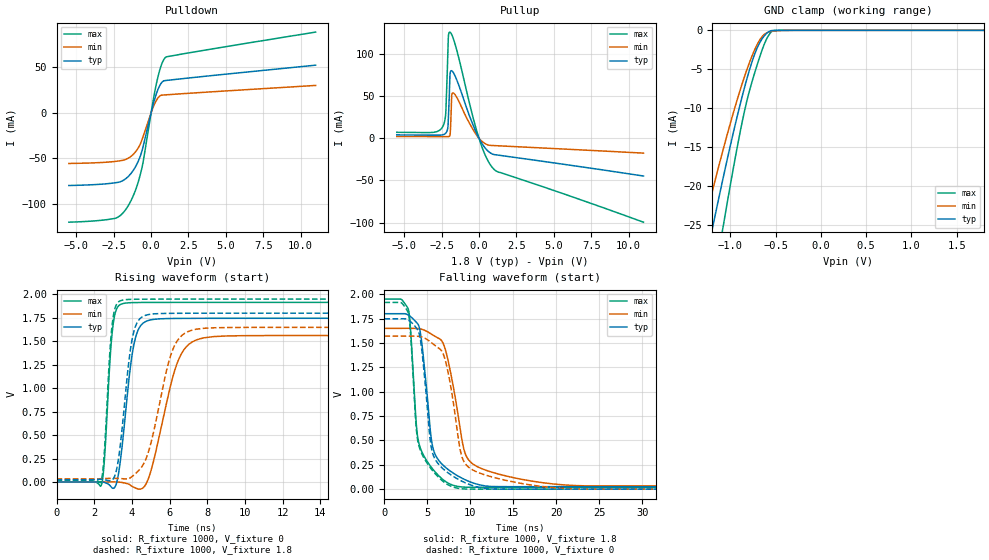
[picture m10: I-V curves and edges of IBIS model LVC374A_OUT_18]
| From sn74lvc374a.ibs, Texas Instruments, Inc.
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[Model]   LVC374A_OUT_18
Model_type  3-state
Enable   Active-Low
Vref =   0
Rref =   1000
Cref =   30p
Vmeas =   0.9
| variable   typ   min   max
C_comp   5.41pF   5.26pF   5.89pF
| C_pullup   6.96pF   5.99pF   7.49pF
| C_pulldown   6.80pF   5.31pF   7.92pF
| C_tri-state   5.41pF   5.26pF   5.89pF
[Temperature Range]   40   100   -40
| Ambient temperature   25   85   -40
[Voltage range]   1.8   1.65   1.95
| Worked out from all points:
|   slope of the pulldown table from 0 to 0.27 V, typ, clamps not added: 16.1 ohm
|   slope of the pullup table from 0 to 0.27 V, typ, clamps not added: 33.2 ohm
|   GND clamp passes 1 mA (typ) near -0.65 V on its own axis
|   rising waveform, R_fixture 1000, V_fixture 0: 20-80 % time 582ps typ, 1.12ns min, 337ps max; typ from 0 V to 1.75 V
|   falling waveform, R_fixture 1000, V_fixture 1.8: 20-80 % time 1.37ns typ, 2.05ns min, 1.16ns max; typ from 1.8 V to 0.026 V
|   rising waveform, R_fixture 1000, V_fixture 1.8: 20-80 % time 572ps typ, 1.09ns min, 332ps max; typ from 0.025 V to 1.8 V
|   falling waveform, R_fixture 1000, V_fixture 0: 20-80 % time 1.3ns typ, 1.83ns min, 1.16ns max; typ from 1.75 V to 0 V
[GND Clamp]
| LVC374A_OUT_18
|   Voltage   I(typ)   I(min)   I(max)
-5.5V     -311.6mA   -259.3mA   -396.4mA
-1.3V     -31.17mA   -25.35mA   -40.84mA
-1.215V   -26.32mA   -21.36mA   -34.65mA
-1.175V   -24.09mA   -19.52mA   -31.79mA
-1.1V     -19.99mA   -16.16mA   -26.53mA
-1.06V    -17.86mA   -14.42mA   -23.79mA
-880mV    -8.928mA   -7.206mA   -12.33mA
-765mV    -4.161mA   -3.399mA   -6.744mA
-655mV    -1.171mA   -880.6uA   -2.683mA
-590mV    -295.4uA   -275.9uA   -882.9uA
-540mV    -28.91uA   -111.9uA   -128.1uA
1.8V      35.26pA    10.02nA    -1.245nA
[Pulldown]
| LVC374A_OUT_18
|   Voltage   I(typ)   I(min)   I(max)
-5.5V     -79.86mA   -55.62mA   -120.2mA
-2.405V   -76.84mA   -53.37mA   -115.9mA
-1.95V    -74.97mA   -52.33mA   -111.2mA
-1.505V   -69.56mA   -49.58mA   -101.4mA
-1.04V    -59.1mA    -42.78mA   -84.85mA
-665mV    -44.74mA   -31.97mA   -64.09mA
-520mV    -36.04mA   -25.31mA   -52.64mA
70mV      4.78mA     3.284mA    7.076mA
355mV     21.12mA    13.82mA    32.13mA
675mV     32.63mA    19.38mA    52.09mA
970mV     35.59mA    19.83mA    61.12mA
11V       52.47mA    30.19mA    88.86mA
[Pullup]
| LVC374A_OUT_18
|   Voltage   I(typ)   I(min)   I(max)
-5.5V     4.132mA    2.28mA     7.221mA
-2.42V    4.318mA    2.093mA    14.19mA
-2.225V   6.276mA    2.078mA    30.14mA
-2.085V   12.97mA    2.077mA    101.8mA
-2.045V   25.72mA    2.109mA    121.9mA
-1.945V   74.01mA    3.627mA    126.3mA
-1.895V   79.92mA    16.59mA    125.6mA
-1.83V    80.38mA    50.38mA    123.6mA
-1.73V    78.5mA     54.05mA    119.2mA
-25mV     874.8uA    531.1uA    1.42mA
995mV     -19.19mA   -8.546mA   -36.64mA
11V       -44.72mA   -17.52mA   -99.61mA
[Ramp]
| LVC374A_OUT_18
| variable   typ   min   max
dV/dt_r   1.09/6.04E-10   0.98/1.16E-09   1.18/3.48E-10
dV/dt_f   1.06/1.37E-09   0.97/2.05E-09   1.16/1.16E-09
R_load = 1000
[Rising Waveform]
| LVC374A_OUT_18
R_fixture =   1000
C_fixture =   0
L_fixture =   0
V_fixture =   0
V_fixture_min = 0
V_fixture_max = 0
|   Time   V(typ)   V(min)   V(max)
0s        658.2pV    3.523nV    28.78nV
2.385ns   92.47uV    -397.2uV   -28.95mV
2.99ns    -66.83mV   626.5uV    1.658V
3.585ns   581.3mV    -9.507mV   1.905V
4.03ns    1.381V     -48.21mV   1.912V
4.465ns   1.666V     -74.95mV   1.913V
5.005ns   1.728V     116.3mV    1.914V
6.48ns    1.744V     1.306V     1.915V
7.89ns    1.745V     1.539V     1.915V
50ns      1.746V     1.563V     1.915V
[Falling Waveform]
| LVC374A_OUT_18
R_fixture =   1000
C_fixture =   0
L_fixture =   0
V_fixture =   1.8
V_fixture_min = 1.65
V_fixture_max = 1.95
|   Time   V(typ)   V(min)   V(max)
0s        1.8V       1.65V      1.95V
2.825ns   1.784V     1.651V     1.83V
3.69ns    1.714V     1.649V     687mV
3.965ns   1.682V     1.647V     487.2mV
5.605ns   437.4mV    1.583V     207.9mV
6.805ns   247.6mV    1.5V       98.88mV
7.695ns   183.5mV    1.198V     50.04mV
9.435ns   94.8mV     357.6mV    20.26mV
12.33ns   27.84mV    178.9mV    19.09mV
50ns      25.51mV    33.86mV    18.78mV
[Rising Waveform]
| LVC374A_OUT_18
R_fixture =   1000
C_fixture =   0
L_fixture =   0
V_fixture =   1.8
V_fixture_min = 1.65
V_fixture_max = 1.95
|   Time   V(typ)   V(min)   V(max)
0s        25.49mV    33.75mV    18.77mV
2.355ns   28.97mV    34.94mV    4.667mV
2.52ns    26.65mV    36.62mV    268.3mV
2.965ns   24.12mV    38.87mV    1.699V
3.52ns    648.7mV    34.8mV     1.939V
3.935ns   1.43V      47.96mV    1.947V
4.33ns    1.717V     116.4mV    1.948V
6.18ns    1.798V     1.417V     1.95V
7.42ns    1.799V     1.629V     1.95V
50ns      1.8V       1.65V      1.95V
[Falling Waveform]
| LVC374A_OUT_18
R_fixture =   1000
C_fixture =   0
L_fixture =   0
V_fixture =   0
V_fixture_min = 0
V_fixture_max = 0
|   Time   V(typ)   V(min)   V(max)
0s        1.748V     1.57V      1.916V
2.82ns    1.732V     1.571V     1.793V
3.665ns   1.658V     1.569V     667.7mV
3.955ns   1.621V     1.568V     463.7mV
5.51ns    401.1mV    1.5V       200.5mV
6.815ns   209.2mV    1.391V     80.67mV
7.72ns    147.8mV    1.05V      31.14mV
9.145ns   76.05mV    302.2mV    3.107mV
12.33ns   1.797mV    129.8mV    310.9uV
50ns      27.5uV     104.9uV    9.822uV
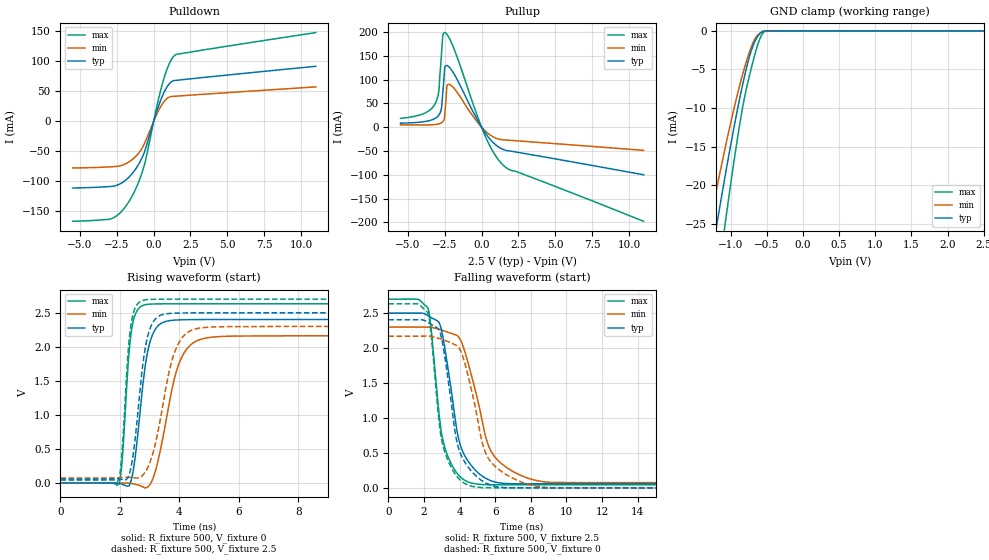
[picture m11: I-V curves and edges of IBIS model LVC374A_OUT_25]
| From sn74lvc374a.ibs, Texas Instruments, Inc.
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[Model]   LVC374A_OUT_25
Model_type  3-state
Enable   Active-Low
Vref =   0
Rref =   500
Cref =   30p
Vmeas =   1.25
| variable   typ   min   max
C_comp   5.34pF   5.06pF   5.85pF
| C_pullup   7.03pF   5.88pF   7.60pF
| C_pulldown   6.50pF   5.15pF   7.89pF
| C_tri-state   5.34pF   5.06pF   5.85pF
[Temperature Range]   40   100   -40
| Ambient temperature   25   85   -40
[Voltage range]   2.5   2.3   2.7
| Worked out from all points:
|   slope of the pulldown table from 0 to 0.375 V, typ, clamps not added: 13 ohm
|   slope of the pullup table from 0 to 0.375 V, typ, clamps not added: 21.5 ohm
|   GND clamp passes 1 mA (typ) near -0.64 V on its own axis
|   rising waveform, R_fixture 500, V_fixture 0: 20-80 % time 389ps typ, 631ps min, 243ps max; typ from 0 V to 2.4 V
|   falling waveform, R_fixture 500, V_fixture 2.5: 20-80 % time 970ps typ, 1.37ns min, 728ps max; typ from 2.5 V to 0.058 V
|   rising waveform, R_fixture 500, V_fixture 2.5: 20-80 % time 380ps typ, 629ps min, 236ps max; typ from 0.058 V to 2.5 V
|   falling waveform, R_fixture 500, V_fixture 0: 20-80 % time 923ps typ, 1.25ns min, 718ps max; typ from 2.4 V to 0 V
[GND Clamp]
| LVC374A_OUT_25
|   Voltage   I(typ)   I(min)   I(max)
-5.5V     -311.6mA   -259.3mA   -396.4mA
-1.31V    -31.75mA   -25.83mA   -41.58mA
-1.265V   -29.16mA   -23.69mA   -38.28mA
-1.22V    -26.61mA   -21.59mA   -35.01mA
-1.175V   -24.09mA   -19.52mA   -31.79mA
-1.095V   -19.72mA   -15.94mA   -26.19mA
-1.06V    -17.86mA   -14.42mA   -23.79mA
-875mV    -8.7mA     -7.025mA   -12.04mA
-760mV    -3.983mA   -3.255mA   -6.545mA
-650mV    -1.084mA   -807.5uA   -2.519mA
-535mV    -25.82uA   -102.9uA   -89.75uA
2.5V      48.15pA    25.99nA    -1.38nA
[Pulldown]
| LVC374A_OUT_25
|   Voltage   I(typ)   I(min)   I(max)
-5.5V     -110.9mA   -77.52mA   -166.4mA
-2.86V    -108.3mA   -75.52mA   -162mA
-2.255V   -103.7mA   -73.72mA   -151.9mA
-1.655V   -92.21mA   -67.04mA   -132.6mA
-1.13V    -75.85mA   -56.02mA   -107.5mA
-700mV    -55.51mA   -40.79mA   -78.33mA
-525mV    -43.32mA   -31.25mA   -62.33mA
245mV     19.49mA    13.85mA    28.34mA
595mV     42.54mA    29.39mA    62.99mA
1.03V     61.88mA    40.37mA    94.77mA
1.435V    68.29mA    42.04mA    110.4mA
11V       91.99mA    57.63mA    148.2mA
[Pullup]
| LVC374A_OUT_25
|   Voltage   I(typ)   I(min)   I(max)
-5.5V     8.51mA     4.863mA    18.58mA
-3.91V    11.55mA    4.714mA    28.82mA
-3.14V    18.79mA    5.666mA    49.97mA
-2.905V   25.32mA    6.979mA    75.87mA
-2.73V    38.61mA    9.098mA    150.1mA
-2.625V   74.51mA    11.69mA    193.3mA
-2.475V   127.2mA    34.48mA    198.8mA
-2.35V    129.6mA    86.31mA    195.3mA
-2.145V   124.6mA    89.55mA    184.5mA
185mV     -9.092mA   -6.052mA   -14.17mA
1.465V    -46.97mA   -26.57mA   -79.91mA
11V       -100.1mA   -48.72mA   -197.9mA
[Ramp]
| LVC374A_OUT_25
| variable   typ   min   max
dV/dt_r   1.47/3.98E-10   1.34/6.52E-10   1.60/2.49E-10
dV/dt_f   1.47/9.71E-10   1.34/1.38E-09   1.59/7.31E-10
R_load = 500
[Rising Waveform]
| LVC374A_OUT_25
R_fixture =   500
C_fixture =   0
L_fixture =   0
V_fixture =   0
V_fixture_min = 0
V_fixture_max = 0
|   Time   V(typ)   V(min)   V(max)
0s        750.8pV    3.045nV    27.79nV
1.975ns   -5.154mV   -421.1uV   -11.64mV
2.08ns    -17.88mV   -198.2uV   357.2mV
2.275ns   -44.6mV    -1.024mV   1.732V
2.395ns   66.55mV    -6.859mV   2.254V
2.915ns   1.883V     -63.32mV   2.623V
3.28ns    2.307V     320.6mV    2.63V
4.03ns    2.396V     1.799V     2.631V
5.095ns   2.401V     2.142V     2.632V
50ns      2.402V     2.163V     2.632V
[Falling Waveform]
| LVC374A_OUT_25
R_fixture =   500
C_fixture =   0
L_fixture =   0
V_fixture =   2.5
V_fixture_min = 2.3
V_fixture_max = 2.7
|   Time   V(typ)   V(min)   V(max)
0s        2.5V       2.3V       2.7V
2.24ns    2.461V     2.3V       2.56V
2.84ns    2.368V     2.268V     1.075V
3.2ns     1.953V     2.239V     550.4mV
3.95ns    696.2mV    2.157V     180.6mV
4.765ns   286.6mV    1.512V     63.16mV
5.49ns    133.7mV    707.3mV    45.87mV
5.9ns     90.51mV    468.9mV    44.59mV
8.74ns    58.56mV    86.99mV    44.09mV
50ns      58.46mV    74.55mV    43.93mV
[Rising Waveform]
| LVC374A_OUT_25
R_fixture =   500
C_fixture =   0
L_fixture =   0
V_fixture =   2.5
V_fixture_min = 2.3
V_fixture_max = 2.7
|   Time   V(typ)   V(min)   V(max)
0s        58.44mV    74.47mV    43.92mV
1.97ns    61.9mV     77.71mV    61.17mV
2.065ns   55.35mV    80.21mV    417.1mV
2.275ns   86.64mV    83.54mV    1.917V
2.38ns    244.7mV    81.23mV    2.346V
2.89ns    2.067V     187.6mV    2.692V
3.21ns    2.417V     609.2mV    2.698V
3.875ns   2.494V     1.959V     2.699V
4.81ns    2.499V     2.283V     2.7V
50ns      2.5V       2.3V       2.7V
[Falling Waveform]
| LVC374A_OUT_25
R_fixture =   500
C_fixture =   0
L_fixture =   0
V_fixture =   0
V_fixture_min = 0
V_fixture_max = 0
|   Time   V(typ)   V(min)   V(max)
0s        2.405V     2.17V      2.633V
2.235ns   2.366V     2.171V     2.492V
2.83ns    2.267V     2.139V     988mV
3.175ns   1.867V     2.109V     509.1mV
3.875ns   629.4mV    2.028V     155.3mV
4.76ns    211.7mV    1.296V     19mV
5.295ns   96.28mV    625.3mV    3.649mV
5.725ns   42.35mV    382.5mV    902.7uV
8.66ns    119.1uV    10.73mV    169.1uV
50ns      25.31uV    72.32uV    8.115uV
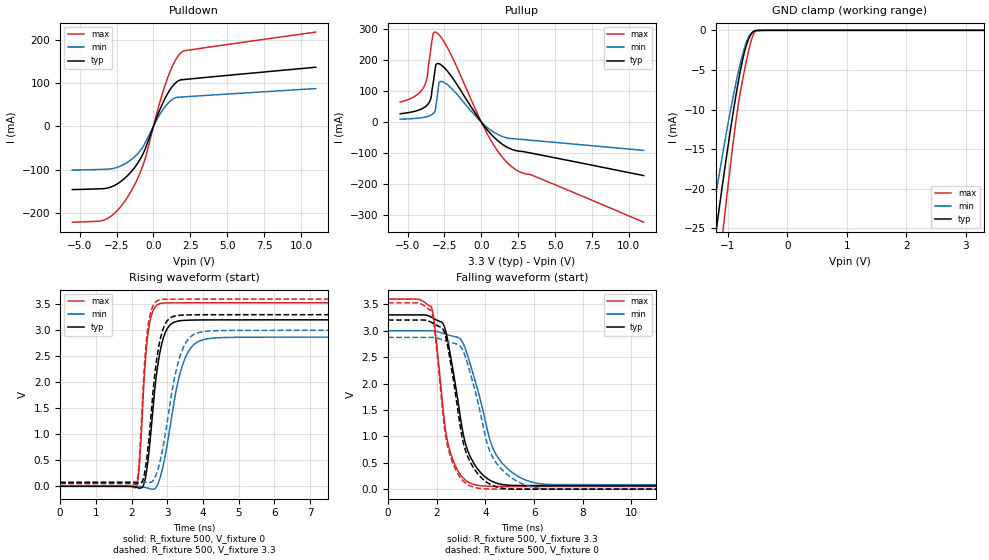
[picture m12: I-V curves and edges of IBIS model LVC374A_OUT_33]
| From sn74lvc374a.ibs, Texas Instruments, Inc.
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[Model]   LVC374A_OUT_33
Model_type  3-state
Enable   Active-Low
Vref =   0
Rref =   500
Cref =   50p
Vmeas =   1.5
| variable   typ   min   max
C_comp   5.34pF   4.94pF   6.74pF
| C_pullup   7.10pF   5.62pF   8.55pF
| C_pulldown   6.33pF   5.00pF   7.32pF
| C_tri-state   5.34pF   4.94pF   6.74pF
[Temperature Range]   40   100   -40
| Ambient temperature   25   85   -40
[Voltage range]   3.3   3   3.6
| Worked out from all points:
|   slope of the pulldown table from 0 to 0.495 V, typ, clamps not added: 11.4 ohm
|   slope of the pullup table from 0 to 0.495 V, typ, clamps not added: 16.4 ohm
|   GND clamp passes 1 mA (typ) near -0.64 V on its own axis
|   rising waveform, R_fixture 500, V_fixture 0: 20-80 % time 307ps typ, 476ps min, 195ps max; typ from 0 V to 3.2 V
|   falling waveform, R_fixture 500, V_fixture 3.3: 20-80 % time 768ps typ, 1.08ns min, 558ps max; typ from 3.3 V to 0.068 V
|   rising waveform, R_fixture 500, V_fixture 3.3: 20-80 % time 298ps typ, 464ps min, 190ps max; typ from 0.068 V to 3.3 V
|   falling waveform, R_fixture 500, V_fixture 0: 20-80 % time 745ps typ, 1.02ns min, 550ps max; typ from 3.2 V to 0 V
[GND Clamp]
| LVC374A_OUT_33
|   Voltage   I(typ)   I(min)   I(max)
-5.5V     -311.6mA   -259.3mA   -396.4mA
-1.31V    -31.75mA   -25.83mA   -41.58mA
-1.265V   -29.16mA   -23.69mA   -38.28mA
-1.18V    -24.37mA   -19.75mA   -32.15mA
-1.095V   -19.72mA   -15.94mA   -26.19mA
-1.055V   -17.59mA   -14.21mA   -23.46mA
-880mV    -8.928mA   -7.206mA   -12.33mA
-760mV    -3.983mA   -3.255mA   -6.545mA
-650mV    -1.084mA   -807.5uA   -2.519mA
-590mV    -295.4uA   -275.9uA   -882.9uA
-535mV    -25.82uA   -102.9uA   -89.75uA
3.3V      62.9pA     44.06nA    -1.528nA
[Pulldown]
| LVC374A_OUT_33
|   Voltage   I(typ)   I(min)   I(max)
-5.5V     -146.4mA   -101.1mA   -221.9mA
-3.68V    -144.6mA   -99.84mA   -219.5mA
-3.245V   -143.7mA   -99.3mA    -215.5mA
-2.51V    -134.3mA   -95.46mA   -197mA
-1.765V   -114.4mA   -83.29mA   -164.4mA
-1.14V    -88.8mA    -65.81mA   -125.6mA
-630mV    -58.01mA   -42.52mA   -82.36mA
385mV     34.5mA     24.73mA    49.95mA
995mV     77.77mA    53.81mA    115.3mA
1.47V     99.56mA    65.75mA    151.8mA
1.91V     107.8mA    67.82mA    171.6mA
11V       136.8mA    87.37mA    218.1mA
[Pullup]
| LVC374A_OUT_33
|   Voltage   I(typ)   I(min)   I(max)
-5.5V     27.15mA    9.676mA    64.84mA
-4.47V    35.52mA    12.08mA    84.48mA
-3.88V    47.09mA    15.63mA    115mA
-3.675V   55mA       17.9mA     145.1mA
-3.43V    75.88mA    22.33mA    234.3mA
-3.27V    125.3mA    27.62mA    284.1mA
-3.065V   185.7mA    57.97mA    288.8mA
-2.875V   188mA      125.7mA    281.3mA
-2.57V    177.9mA    129.2mA    261.6mA
385mV     -24.04mA   -16.62mA   -36.62mA
1.895V    -84.17mA   -52.11mA   -136.8mA
11V       -171.9mA   -90.86mA   -321.9mA
[Ramp]
| LVC374A_OUT_33
| variable   typ   min   max
dV/dt_r   1.94/3.18E-10   1.75/4.85E-10   2.13/1.98E-10
dV/dt_f   1.94/7.72E-10   1.75/1.08E-09   2.13/5.58E-10
R_load = 500
[Rising Waveform]
| LVC374A_OUT_33
R_fixture =   500
C_fixture =   0
L_fixture =   0
V_fixture =   0
V_fixture_min = 0
V_fixture_max = 0
|   Time   V(typ)   V(min)   V(max)
0s        876.5pV    2.928nV    28.8nV
2.13ns    -17.23mV   -623.5uV   -13.29mV
2.21ns    -36.34mV   -3.147mV   331.9mV
2.375ns   118.1mV    -22.03mV   2.295V
2.48ns    617.6mV    -39.87mV   3.031V
2.695ns   2.129V     -12.55mV   3.474V
2.89ns    2.849V     412mV      3.523V
3.49ns    3.191V     2.446V     3.528V
4.335ns   3.2V       2.852V     3.528V
50ns      3.201V     2.87V      3.529V
[Falling Waveform]
| LVC374A_OUT_33
R_fixture =   500
C_fixture =   0
L_fixture =   0
V_fixture =   3.3
V_fixture_min = 3
V_fixture_max = 3.6
|   Time   V(typ)   V(min)   V(max)
0s        3.3V       3V         3.6V
1.77ns    3.26V      3.001V     3.455V
2.26ns    3.13V      2.949V     1.519V
2.46ns    2.799V     2.921V     869.6mV
2.775ns   1.956V     2.885V     432.8mV
3.18ns    863.3mV    2.651V     170.6mV
3.715ns   361.1mV    1.825V     70.61mV
4.545ns   102.7mV    576.5mV    52.81mV
6.43ns    68.27mV    93.57mV    52.15mV
50ns      68.11mV    84.91mV    51.97mV
[Rising Waveform]
| LVC374A_OUT_33
R_fixture =   500
C_fixture =   0
L_fixture =   0
V_fixture =   3.3
V_fixture_min = 3
V_fixture_max = 3.6
|   Time   V(typ)   V(min)   V(max)
0s        68.08mV    84.86mV    51.96mV
2.13ns    61.56mV    90.55mV    54.56mV
2.205ns   50.21mV    91.63mV    403.2mV
2.36ns    239.7mV    82.05mV    2.32V
2.46ns    741.8mV    75.11mV    3.071V
2.66ns    2.205V     177mV      3.533V
2.825ns   2.889V     561.5mV    3.591V
3.4ns     3.291V     2.583V     3.599V
4.155ns   3.299V     2.984V     3.6V
50ns      3.3V       3V         3.6V
[Falling Waveform]
| LVC374A_OUT_33
R_fixture =   500
C_fixture =   0
L_fixture =   0
V_fixture =   0
V_fixture_min = 0
V_fixture_max = 0
|   Time   V(typ)   V(min)   V(max)
0s        3.203V     2.875V     3.53V
1.77ns    3.162V     2.875V     3.381V
2.255ns   3.03V      2.824V     1.417V
2.535ns   2.481V     2.784V     663.6mV
3.095ns   869.2mV    2.607V     150.3mV
3.71ns    278.7mV    1.609V     18.42mV
4.1ns     116.7mV    822.8mV    3.922mV
4.485ns   38.81mV    471.6mV    963.4uV
6.395ns   183uV      7.783mV    182.7uV
50ns      24.78uV    47.2uV     7.422uV
